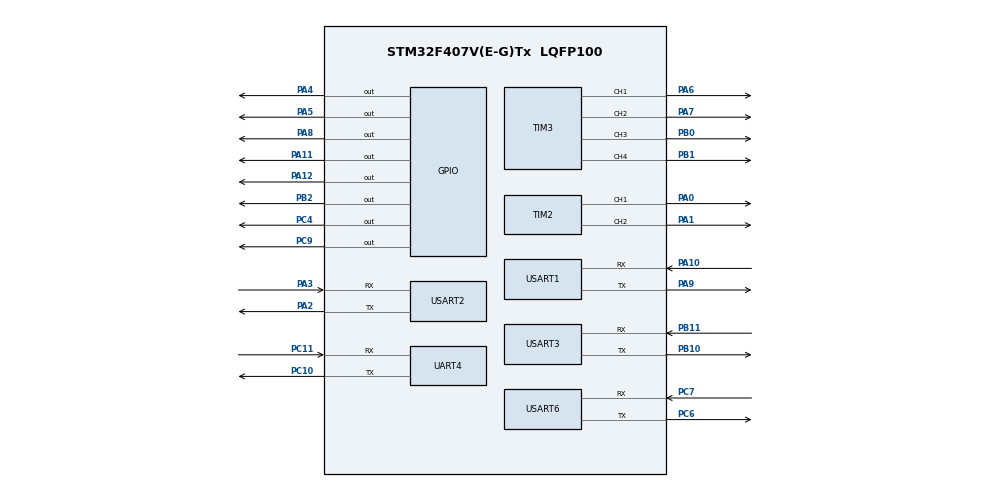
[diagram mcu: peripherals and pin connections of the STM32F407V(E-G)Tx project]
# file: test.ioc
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FREERTOS.Queues01=uart1_rx_queue,16,64,1,Dynamic,NULL,NULL;uart2_rx_queue,16,64,1,Dynamic,NULL,NULL;uart3_rx_queue,16,64,1,Dynamic,NULL,NULL;parsed_cmd_queue,16,64,1,Dynamic,NULL,NULL;status_queue,16,64,1,Dynamic,NULL,NULL
FREERTOS.Tasks01=defaultTask,24,128,StartDefaultTask,Default,NULL,Dynamic,NULL,NULL;Receive_Task,11,256,CommReceiveEntry,Default,NULL,Dynamic,NULL,NULL;Sensor_Task,12,512,SensorProcessEntry,Default,NULL,Dynamic,NULL,NULL;Control_Task,14,768,ControlEntry,Default,NULL,Dynamic,NULL,NULL;Send_Task,10,512,CommSendEntry,Default,NULL,Dynamic,NULL,NULL;Parse_Task,11,384,ParseEntry,Default,NULL,Dynamic,NULL,NULL;Status_Task,10,256,StatusEntry,Default,NULL,Dynamic,NULL,NULL
FREERTOS.configTOTAL_HEAP_SIZE=32768
Mcu.Family=STM32F4
Mcu.Name=STM32F407V(E-G)Tx
Mcu.Package=LQFP100
NVIC.PriorityGroup=NVIC_PRIORITYGROUP_4
NVIC.TIM1_UP_TIM10_IRQn=true\:15\:0\:false\:false\:true\:false\:false\:true\:true
NVIC.TimeBase=TIM1_UP_TIM10_IRQn
NVIC.TimeBaseIP=TIM1
NVIC.UART4_IRQn=true\:5\:0\:false\:false\:true\:true\:true\:true\:true
NVIC.USART1_IRQn=true\:5\:0\:false\:false\:true\:true\:true\:true\:true
NVIC.USART2_IRQn=true\:5\:0\:false\:false\:true\:true\:true\:true\:true
NVIC.USART3_IRQn=true\:5\:0\:false\:false\:true\:true\:true\:true\:true
NVIC.USART6_IRQn=true\:5\:0\:false\:false\:true\:true\:true\:true\:true
PA0-WKUP.Signal=S_TIM2_CH1_ETR
PA1.Signal=S_TIM2_CH2
PA10.Mode=Asynchronous
PA10.Signal=USART1_RX
PA11.GPIO_Speed=GPIO_SPEED_FREQ_MEDIUM
PA11.Signal=GPIO_Output
PA12.GPIO_Speed=GPIO_SPEED_FREQ_MEDIUM
PA12.Signal=GPIO_Output
PA13.Mode=Serial_Wire
PA13.Signal=SYS_JTMS-SWDIO
PA14.Mode=Serial_Wire
PA14.Signal=SYS_JTCK-SWCLK
PA2.Mode=Asynchronous
PA2.Signal=USART2_TX
PA3.Mode=Asynchronous
PA3.Signal=USART2_RX
PA4.GPIO_ModeDefaultOutputPP=GPIO_MODE_OUTPUT_OD
PA4.GPIO_PuPd=GPIO_NOPULL
PA4.GPIO_Speed=GPIO_SPEED_FREQ_HIGH
PA4.Signal=GPIO_Output
PA5.GPIO_ModeDefaultOutputPP=GPIO_MODE_OUTPUT_OD
PA5.GPIO_PuPd=GPIO_NOPULL
PA5.GPIO_Speed=GPIO_SPEED_FREQ_HIGH
PA5.Signal=GPIO_Output
PA6.Signal=S_TIM3_CH1
PA7.Signal=S_TIM3_CH2
PA8.GPIO_ModeDefaultOutputPP=GPIO_MODE_OUTPUT_OD
PA8.GPIO_PuPd=GPIO_NOPULL
PA8.GPIO_Speed=GPIO_SPEED_FREQ_HIGH
PA8.Signal=GPIO_Output
PA9.Mode=Asynchronous
PA9.Signal=USART1_TX
PB0.Signal=S_TIM3_CH3
PB1.Signal=S_TIM3_CH4
PB10.Mode=Asynchronous
PB10.Signal=USART3_TX
PB11.Mode=Asynchronous
PB11.Signal=USART3_RX
PB2.GPIO_Speed=GPIO_SPEED_FREQ_HIGH
PB2.Signal=GPIO_Output
PC10.Mode=Asynchronous
PC10.Signal=UART4_TX
PC11.Mode=Asynchronous
PC11.Signal=UART4_RX
PC4.GPIO_Speed=GPIO_SPEED_FREQ_MEDIUM
PC4.Signal=GPIO_Output
PC6.Mode=Asynchronous
PC6.Signal=USART6_TX
PC7.Mode=Asynchronous
PC7.Signal=USART6_RX
PC9.GPIO_ModeDefaultOutputPP=GPIO_MODE_OUTPUT_OD
PC9.GPIO_PuPd=GPIO_NOPULL
PC9.GPIO_Speed=GPIO_SPEED_FREQ_HIGH
PC9.Signal=GPIO_Output
PH0-OSC_IN.Mode=HSE-External-Oscillator
PH0-OSC_IN.Signal=RCC_OSC_IN
PH1-OSC_OUT.Mode=HSE-External-Oscillator
PH1-OSC_OUT.Signal=RCC_OSC_OUT
ProjectManager.HeapSize=0x200
ProjectManager.StackSize=0x400
ProjectManager.TargetToolchain=MDK-ARM V5.32
RCC.48MHZClocksFreq_Value=84000000
RCC.AHBFreq_Value=168000000
RCC.APB1CLKDivider=RCC_HCLK_DIV4
RCC.APB1Freq_Value=42000000
RCC.APB1TimFreq_Value=84000000
RCC.APB2CLKDivider=RCC_HCLK_DIV2
RCC.APB2Freq_Value=84000000
RCC.APB2TimFreq_Value=168000000
RCC.CortexFreq_Value=168000000
RCC.EnbaleCSS=true
RCC.HCLKFreq_Value=168000000
RCC.HSE_VALUE=8000000
RCC.HSI_VALUE=16000000
RCC.LSE_VALUE=32768
RCC.PLLM=4
RCC.PLLN=168
RCC.PLLSourceVirtual=RCC_PLLSOURCE_HSE
RCC.SYSCLKFreq_VALUE=168000000
RCC.SYSCLKSource=RCC_SYSCLKSOURCE_PLLCLK
RCC.VCOOutputFreq_Value=336000000
SH.S_TIM2_CH1_ETR.0=TIM2_CH1,PWM Generation1 CH1
SH.S_TIM2_CH2.0=TIM2_CH2,PWM Generation2 CH2
SH.S_TIM3_CH1.0=TIM3_CH1,PWM Generation1 CH1
SH.S_TIM3_CH2.0=TIM3_CH2,PWM Generation2 CH2
SH.S_TIM3_CH3.0=TIM3_CH3,PWM Generation3 CH3
SH.S_TIM3_CH4.0=TIM3_CH4,PWM Generation4 CH4
TIM2.Channel-PWM\ Generation1\ CH1=TIM_CHANNEL_1
TIM2.Channel-PWM\ Generation2\ CH2=TIM_CHANNEL_2
TIM3.Channel-PWM\ Generation1\ CH1=TIM_CHANNEL_1
TIM3.Channel-PWM\ Generation2\ CH2=TIM_CHANNEL_2
TIM3.Channel-PWM\ Generation3\ CH3=TIM_CHANNEL_3
TIM3.Channel-PWM\ Generation4\ CH4=TIM_CHANNEL_4
UART4.VirtualMode=Asynchronous
USART1.VirtualMode=VM_ASYNC
USART2.VirtualMode=VM_ASYNC
USART3.VirtualMode=VM_ASYNC
USART6.VirtualMode=VM_ASYNC
VP_FREERTOS_VS_CMSIS_V2.Mode=CMSIS_V2
VP_SYS_VS_tim1.Mode=TIM1
VP_TIM2_VS_ClockSourceINT.Mode=Internal
VP_TIM3_VS_ClockSourceINT.Mode=Internal
board=custom

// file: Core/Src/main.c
/* USER CODE BEGIN Header */
/**
  ******************************************************************************
  * @file           : main.c
  * @brief          : Main program body
  ******************************************************************************
  * @attention
  *
  * Copyright (c) 2025 STMicroelectronics.
  * All rights reserved.
  *
  * This software is licensed under terms that can be found in the LICENSE file
  * in the root directory of this software component.
  * If no LICENSE file comes with this software, it is provided AS-IS.
  *
  ******************************************************************************
  */
/* USER CODE END Header */
#include "main.h"
#include "cmsis_os.h"

#include "tim.h"
#include "usart.h"
#include "gpio.h"

/* USER CODE BEGIN Includes */
#include "stdio.h"
#include "string.h"
#include "RF1.H"
#include "bluebooth.h"
#include "servo.h"
/* USER CODE END Includes */

/* USER CODE BEGIN PD */
// 缓冲区 & 队列句柄
uint8_t uart1_rx_byte;
uint8_t uart1_rx_buf[CMD_LEN+1];
uint8_t uart1_rx_index = 0;
uint8_t uart6_rx_byte;
uint8_t uart3_rx_byte;
uint8_t uart3_rx_buffer[64];
uint8_t uart3_rx_index = 0;
extern osMessageQueueId_t uart1_rx_queueHandle;
extern osMessageQueueId_t uart3_rx_queueHandle;
/* USER CODE END PD */

void SystemClock_Config(void);
void MX_FREERTOS_Init(void);
/* USER CODE BEGIN PFP */
void CopeData(unsigned char ucData);
/* USER CODE END PFP */

/* USER CODE BEGIN 0 */
int fputc(int ch, FILE *f)
{
//	HAL_UART_Transmit(&huart2, (uint8_t *)&ch, 1, HAL_MAX_DELAY);
	HAL_UART_Transmit(&huart1, (uint8_t *)&ch, 1, HAL_MAX_DELAY);
    HAL_UART_Transmit(&huart3, (uint8_t *)&ch, 1, HAL_MAX_DELAY);
//	HAL_UART_Transmit(&huart4, (uint8_t *)&ch, 1, HAL_MAX_DELAY);
//	HAL_UART_Transmit(&huart6, (uint8_t *)&ch, 1, HAL_MAX_DELAY);
    return ch;
}

/* USER CODE END 0 */

int main(void)
{

  /* MCU Configuration--------------------------------------------------------*/

  /* Reset of all peripherals, Initializes the Flash interface and the Systick. */
  HAL_Init();

  /* Configure the system clock */
  SystemClock_Config();

  /* Initialize all configured peripherals */
  MX_GPIO_Init();
  MX_UART4_Init();
  MX_USART1_UART_Init();
  MX_USART6_UART_Init();
  MX_USART2_UART_Init();
  MX_USART3_UART_Init();
  MX_TIM2_Init();
  MX_TIM3_Init();
  /* USER CODE BEGIN 2 */
//  char testMsg[] = "USART2 Test: Hello World!\r\n";
//  uint8_t number = 42;
//  char numStr[10];
    HAL_Delay(100);  // 给IMU上电
//	Sensors_Init();
	HAL_UART_Receive_IT(&huart1, &uart1_rx_byte, 1);
	HAL_UART_Receive_IT(&huart6, &uart6_rx_byte, 1);
	HAL_UART_Receive_IT(&huart3, &uart3_rx_byte, 1);
	Sensors_Init();
	RF_Init();
	bluetooth_Init();
	Servo_Init();
	Motor_Init();
	set_pwm(&htim3, TIM_CHANNEL_1, 7.5f);
	set_pwm(&htim3, TIM_CHANNEL_2, 7.5f);
	set_pwm(&htim3, TIM_CHANNEL_3, 7.5f);
	set_pwm(&htim3, TIM_CHANNEL_4, 7.5f);

//  printf("IMU Initialization Started...\n");
  /* USER CODE END 2 */

  /* Init scheduler */
  osKernelInitialize();

  /* Call init function for freertos objects (in cmsis_os2.c) */
  MX_FREERTOS_Init();

  /* Start scheduler */
  osKernelStart();

  /* We should never get here as control is now taken by the scheduler */

  /* Infinite loop */
  while (1)
  {
    /* USER CODE BEGIN 3 */
//        HAL_UART_Transmit(&huart2, (uint8_t*)testMsg, strlen(testMsg), 100);

//        sprintf(numStr, "Decimal: %d\r\n", number);
//        HAL_UART_Transmit(&huart2, (uint8_t*)numStr, strlen(numStr), 100);

        HAL_Delay(1000);  //
  }
  /* USER CODE END 3 */
}

void SystemClock_Config(void)
{
  RCC_OscInitTypeDef RCC_OscInitStruct = {0};
  RCC_ClkInitTypeDef RCC_ClkInitStruct = {0};

  /** Configure the main internal regulator output voltage
  */
  __HAL_RCC_PWR_CLK_ENABLE();
  __HAL_PWR_VOLTAGESCALING_CONFIG(PWR_REGULATOR_VOLTAGE_SCALE1);

  /** Initializes the RCC Oscillators according to the specified parameters
  * in the RCC_OscInitTypeDef structure.
  */
  RCC_OscInitStruct.OscillatorType = RCC_OSCILLATORTYPE_HSE;
  RCC_OscInitStruct.HSEState = RCC_HSE_ON;
  RCC_OscInitStruct.PLL.PLLState = RCC_PLL_ON;
  RCC_OscInitStruct.PLL.PLLSource = RCC_PLLSOURCE_HSE;
  RCC_OscInitStruct.PLL.PLLM = 4;
  RCC_OscInitStruct.PLL.PLLN = 168;
  RCC_OscInitStruct.PLL.PLLP = RCC_PLLP_DIV2;
  RCC_OscInitStruct.PLL.PLLQ = 4;
  if (HAL_RCC_OscConfig(&RCC_OscInitStruct) != HAL_OK)
  {
    Error_Handler();
  }

  /** Initializes the CPU, AHB and APB buses clocks
  */
  RCC_ClkInitStruct.ClockType = RCC_CLOCKTYPE_HCLK|RCC_CLOCKTYPE_SYSCLK
                              |RCC_CLOCKTYPE_PCLK1|RCC_CLOCKTYPE_PCLK2;
  RCC_ClkInitStruct.SYSCLKSource = RCC_SYSCLKSOURCE_PLLCLK;
  RCC_ClkInitStruct.AHBCLKDivider = RCC_SYSCLK_DIV1;
  RCC_ClkInitStruct.APB1CLKDivider = RCC_HCLK_DIV2;
  RCC_ClkInitStruct.APB2CLKDivider = RCC_HCLK_DIV1;

  if (HAL_RCC_ClockConfig(&RCC_ClkInitStruct, FLASH_LATENCY_5) != HAL_OK)
  {
    Error_Handler();
  }

  /** Enables the Clock Security System
  */
  HAL_RCC_EnableCSS();

}

/* USER CODE BEGIN 4 */
// 中断回调：每收到一帧就入队
/* USER CODE BEGIN 4 */
void HAL_UART_RxCpltCallback(UART_HandleTypeDef *huart)
{
//    if (huart->Instance == USART2)
//    {
//        // 处理USART2接收
//        if (uart2_rx_byte == '\n' || uart2_rx_index >= QUEUE_MSG_SIZE - 1)
//        {
//            uart2_rx_buf[uart2_rx_index] = '\0';  // 结束符

//            // 拷贝缓冲内容，避免覆盖
//            char temp[QUEUE_MSG_SIZE] = {0};
//            memcpy(temp, uart2_rx_buf, QUEUE_MSG_SIZE);

//            // 入队列
//            osMessageQueuePut(uart2_rx_queueHandle, temp, 0, 0);

//            uart2_rx_index = 0;
//        }
//        else
//        {
//            uart2_rx_buf[uart2_rx_index++] = uart2_rx_byte;
//        }

//        // 继续接收下一个字节
//        HAL_UART_Receive_IT(&huart2, &uart2_rx_byte, 1);
//}
	if (huart->Instance == USART6)
    {
        // 处理IMU数据
        CopeData(uart6_rx_byte); // 调用IMU数据处理函数
        // 继续接收下一个字节
        HAL_UART_Receive_IT(&huart6, &uart6_rx_byte, 1);
	}
if (huart->Instance == USART3) {
    static uint8_t buffer[64];
    static uint8_t index = 0;

    // 检测结束符(回车或最大长度)
    if (uart3_rx_byte == '\n' || uart3_rx_byte == '\r') {
         if (index > 0) { // 确保有数据才处理
                buffer[index] = '\0';  // 确保终止符
                osMessageQueuePut(uart3_rx_queueHandle, buffer, 0, 0);
            }
            index = 0;  // 重置索引
    }
    // 处理可打印字符
    else if (uart3_rx_byte >= ' ' && uart3_rx_byte <= '~') {
			if (index < sizeof(buffer) - 1) {
                buffer[index++] = uart3_rx_byte;
            }
	}

//    // 重要修改：处理"GL"和"GR"指令
//    // 条件修正：添加对GL/GR指令的支持
//    if ((buffer[0] == 'G' && (buffer[1] == 'A' || buffer[1] == 'L' || buffer[1] == 'R')) ||
//        (buffer[0] == 'S' && buffer[1] == '4')) {
//        osMessageQueuePut(uart3_rx_queueHandle, buffer, 0, 0);
//    }

    HAL_UART_Receive_IT(huart, &uart3_rx_byte, 1);  // 重新启用接收
}
}

/* USER CODE END 4 *//* USER CODE END 4 */

void HAL_TIM_PeriodElapsedCallback(TIM_HandleTypeDef *htim)
{
  if (htim->Instance == TIM1)
  {
    HAL_IncTick();
  }
}

void Error_Handler(void)
{
  __disable_irq();
  while (1)
  {
  }
}

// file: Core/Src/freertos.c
/* USER CODE BEGIN Header */
/**
  ******************************************************************************
  * File Name          : freertos.c
  * Description        : Code for freertos applications
  ******************************************************************************
  * @attention
  *
  * Copyright (c) 2025 STMicroelectronics.
  * All rights reserved.
  *
  * This software is licensed under terms that can be found in the LICENSE file
  * in the root directory of this software component.
  * If no LICENSE file comes with this software, it is provided AS-IS.
  *
  ******************************************************************************
  */
/* USER CODE END Header */

#include "FreeRTOS.h"
#include "task.h"
#include "main.h"
#include "cmsis_os.h"

/* USER CODE BEGIN Includes */
#include "usart.h"
#include "stdio.h"
#include <string.h>
#include <stdlib.h>
/* USER CODE END Includes */

/* USER CODE BEGIN PTD */
#include "sensors.h"
#include "RF1.h"
#include "bluebooth.h"
#include "servo.h"
#include <stdarg.h>
typedef struct {
    RF_PacketType sensorType;  // 传感器类型标识
    union {
        IMU_Data imu;          // IMU传感器数据
        MS5837_Data depth;     // 深度传感器数据
        INA226_Data power;     // 电源传感器数据
    } data;
} SensorMessage_t;
extern volatile SwimDirection turn_direction;
volatile uint8_t Flag_Servo = 0xFF;
uint8_t Flag_X = 0;
uint8_t Flag_Z = 0xFF;
osMutexId_t servoMutex;
osMutexId_t cruiseMutex; 		// 新增巡航控制互斥锁
/* USER CODE END PTD */

/* USER CODE BEGIN Variables */
osMutexId_t uartMutex;  //串口输出互斥锁
/* USER CODE END Variables */
/* Definitions for defaultTask */
osThreadId_t defaultTaskHandle;
const osThreadAttr_t defaultTask_attributes = {
  .name = "defaultTask",
  .stack_size = 128 * 4,
  .priority = (osPriority_t) osPriorityNormal,
};

/* Definitions for Sensor_Task */
osThreadId_t Sensor_TaskHandle;
const osThreadAttr_t Sensor_Task_attributes = {
  .name = "Sensor_Task",
  .stack_size = 2048 * 4,
  .priority = (osPriority_t) osPriorityNormal,//原来是osPriorityNormal
};

/* Definitions for Parse_Task */
osThreadId_t Parse_TaskHandle;
const osThreadAttr_t Parse_Task_attributes = {
  .name = "Parse_Task",
  .stack_size = 384 * 4,
  .priority = (osPriority_t) osPriorityNormal1,
};
/* Definitions for Status_Task */
osThreadId_t Status_TaskHandle;
const osThreadAttr_t Status_Task_attributes = {
  .name = "Status_Task",
  .stack_size = 256 * 4,
  .priority = (osPriority_t) osPriorityLow2,
};
/* Definitions for uart1_rx_queue */
osMessageQueueId_t uart1_rx_queueHandle;
const osMessageQueueAttr_t uart1_rx_queue_attributes = {
  .name = "uart1_rx_queue"
};
/* Definitions for uart2_rx_queue */
osMessageQueueId_t uart2_rx_queueHandle;
const osMessageQueueAttr_t uart2_rx_queue_attributes = {
  .name = "uart2_rx_queue"
};
/* Definitions for uart3_rx_queue */
osMessageQueueId_t uart3_rx_queueHandle;
const osMessageQueueAttr_t uart3_rx_queue_attributes = {
  .name = "uart3_rx_queue"
};
/* Definitions for parsed_cmd_queue */
osMessageQueueId_t parsed_cmd_queueHandle;
const osMessageQueueAttr_t parsed_cmd_queue_attributes = {
  .name = "parsed_cmd_queue"
};
/* Definitions for status_queue */
osMessageQueueId_t status_queueHandle;
const osMessageQueueAttr_t status_queue_attributes = {
  .name = "status_queue"
};
osMessageQueueId_t servo_cmd_queueHandle;
const osMessageQueueAttr_t servo_cmd_queue_attributes = {
    .name = "servo_cmd_queue"
};
/* USER CODE BEGIN FunctionPrototypes */
void parse_command(const char *cmd, uint8_t port_id);
void SafePrintf(const char *format, ...);
void SafePrintf(const char *format, ...)
{
    if (osMutexAcquire(uartMutex,100) == osOK) {  // 最多等待100ms
        va_list args;
        va_start(args, format);
        vprintf(format, args);
        va_end(args);
        osMutexRelease(uartMutex);
    }
}
/* USER CODE END FunctionPrototypes */

void StartDefaultTask(void *argument);
void CommReceiveEntry(void *argument);
void SensorProcessEntry(void *argument);
void CommSendEntry(void *argument);
//void ParseEntry(void *argument);
//void StatusEntry(void *argument);
void MX_FREERTOS_Init(void); /* (MISRA C 2004 rule 8.1) */

void MX_FREERTOS_Init(void) {

  /* Create the queue(s) */
  /* creation of uart1_rx_queue */
  uart1_rx_queueHandle = osMessageQueueNew (16, 64, &uart1_rx_queue_attributes);

  /* creation of uart2_rx_queue */
  uart2_rx_queueHandle = osMessageQueueNew (16, QUEUE_MSG_SIZE, &uart2_rx_queue_attributes);

  /* creation of uart3_rx_queue */
  uart3_rx_queueHandle = osMessageQueueNew (16, 64, &uart3_rx_queue_attributes);

  /* creation of parsed_cmd_queue */
  parsed_cmd_queueHandle = osMessageQueueNew (16, 64, &parsed_cmd_queue_attributes);

  /* creation of status_queue */
  status_queueHandle = osMessageQueueNew (16, 64, &status_queue_attributes);

  /* Create the thread(s) */
  /* creation of defaultTask */
  defaultTaskHandle = osThreadNew(StartDefaultTask, NULL, &defaultTask_attributes);

  /* creation of Sensor_Task */
  Sensor_TaskHandle = osThreadNew(SensorProcessEntry, NULL, &Sensor_Task_attributes);

//  /* creation of Parse_Task */
//  Parse_TaskHandle = osThreadNew(ParseEntry, NULL, &Parse_Task_attributes);

//  /* creation of Status_Task */
//  Status_TaskHandle = osThreadNew(StatusEntry, NULL, &Status_Task_attributes);

uartMutex = osMutexNew(NULL);
  if (uartMutex == NULL) {
    // 互斥锁创建失败处理（系统关键错误）
    Error_Handler();
  }
  servoMutex = osMutexNew(NULL);
  cruiseMutex = osMutexNew(NULL);

}

void StartDefaultTask(void *argument)
{
  /* USER CODE BEGIN StartDefaultTask */
  /* Infinite loop */
  for(;;)
  {
		UpdatePropellers();
		osMutexAcquire(servoMutex, osWaitForever);
        uint8_t local_flag = Flag_Servo;
        SwimDirection local_turn_direction = turn_direction;
        osMutexRelease(servoMutex);
		// 获取当前巡航状态
		uint8_t cruise_active = 0;
		osMutexAcquire(cruiseMutex, osWaitForever);
		cruise_active = cruise_control.active;
		osMutexRelease(cruiseMutex);
	if (cruise_active) {
        // 巡航模式优先
        Cruise_Update(); // 在互斥锁保护下更新
    }
	else {
            if (local_turn_direction == DIRECTION_FORWARD) {
                Servo_ForwardTask();
            }
            else if (local_turn_direction == DIRECTION_LEFT ||
                     local_turn_direction == DIRECTION_RIGHT) {
                Servo_UpdateTask();
            }
            else if (local_turn_direction == DIRECTION_STOP) {
            // 确保舵机保持停止状态
            static uint32_t last_stop_check = 0;
            if (HAL_GetTick() - last_stop_check > 1000) {
                Servo_Stop(); // 每秒检查一次
                last_stop_check = HAL_GetTick();
            }
            }
		}
		if (Flag_Z == 0xFF) {
            // 未收到指令，保持初始值 8.5f
            static uint32_t last_check = 0;
            if(HAL_GetTick() - last_check > 1000) {
                set_pwm(&htim3, TIM_CHANNEL_4, 9.5f);
                last_check = HAL_GetTick();
            }
        }
	   else if (Flag_Z == 0)
	  {
		 set_pwm(&htim3, TIM_CHANNEL_4, 4.5f);
	  }
	  	  else if (Flag_Z == 1) {
		 set_pwm(&htim3, TIM_CHANNEL_4, 5.5f);
        }
	  	 else if (Flag_Z == 2) {
		set_pwm(&htim3, TIM_CHANNEL_4, 6.5f);
        }
		else if (Flag_Z == 3) {
        set_pwm(&htim3, TIM_CHANNEL_4, 7.5f);
    }
		else if (Flag_Z == 4) {
        set_pwm(&htim3, TIM_CHANNEL_4, 8.5f);
    }
	else if (Flag_Z == 5) {
        set_pwm(&htim3, TIM_CHANNEL_4, 9.5f);
    }
	 else if (Flag_Z == 6) {
        set_pwm(&htim3, TIM_CHANNEL_4, 10.5f);
    }
	 else if (Flag_Z == 7) {
        set_pwm(&htim3, TIM_CHANNEL_4, 11.5f);
    }
	else if (Flag_Z == 8) {
        set_pwm(&htim3, TIM_CHANNEL_4, 13.5f);
    }
	else if (Flag_Z == 9) {
        set_pwm(&htim3, TIM_CHANNEL_4, 35.5f);
    } osDelay(10);
	}
}
  /* USER CODE END StartDefaultTask */

void CommReceiveEntry(void *argument)
{
  /* USER CODE BEGIN CommReceiveEntry */
  /* Infinite loop */
	char rx_buffer[64]; // 使用局部缓冲区
    for (;;) {
        if (osMessageQueueGet(uart3_rx_queueHandle, rx_buffer, NULL, 50) == osOK) {
            // 快速处理指令

            char cmd[3] = {rx_buffer[0], rx_buffer[1],  '\0'};
            parse_command(cmd, 2);
        }

        osDelay(50);
    }
}

void SensorProcessEntry(void *argument)
{
	/* USER CODE BEGIN SensorProcessEntry */
	/* Infinite loop */
	SensorData_t sensor_data;
	TickType_t lastWakeTime = xTaskGetTickCount();
  for(;;)
  {
// 读取传感器数据
    Sensor_ReadAll(&sensor_data);
// 使用单个printf输出所有关键传感器数据
		SafePrintf(
            "fish_attitude: {\n"
            "  roll: %.10f,\n"
            "  pitch: %.10f,\n"
            "  yaw: %.10f,\n"
            "  roll_speed: %.10f,\n"
            "  pitch_speed: %.10f,\n"
            "  yaw_speed: %.10f\n"
            "},\n"
            "depth_sensor: {"
            "  depth: %.4fcm,"
            "  temperature: %.2f,"
            "  pressure: %.2fpa"
            "},\n"
            "power_sensor: {"
            "  voltage: %umV,"
            "  current: %umA,"
            "  power: %umW""},\n",
            // 姿态数据
            sensor_data.roll,
            sensor_data.pitch,
            sensor_data.yaw,
            sensor_data.wx,
            sensor_data.wy,
            sensor_data.wz,
            // 深度传感器数据
            sensor_data.depth,
            sensor_data.temperature,
            sensor_data.pressure,
          // 电源传感器数据
            sensor_data.bus_voltage,
            sensor_data.current,
            sensor_data.power
			);
	vTaskDelayUntil(&lastWakeTime, pdMS_TO_TICKS(10));
  }

  /* USER CODE END SensorProcessEntry */
}

void parse_command(const char *cmd, uint8_t port_id)
{
// 仅打印原始指令

	SafePrintf("CMD: %s\r\n", cmd);

	if (strlen(cmd) == 2)
    {
        // D系列指令 - 舵机控制
        if (cmd[0] == 'D') {
            osMutexAcquire(servoMutex, osWaitForever);

            switch(cmd[1]) {
                case '0': // 停止
					Flag_Servo = 0;
                    turn_direction = DIRECTION_STOP;
                    Servo_Stop();  // 直接调用停止函数
                    printf("Servo stop command received\n");
                    break;

                case '1': // 前进
                    Flag_Servo = 1;
                    turn_direction = DIRECTION_FORWARD;
                    // 重置状态机
                    current_state_x = PWM_STATE_DUTY1;
                    last_jiao_switch_time = HAL_GetTick();
                    printf("Servo forward command received\n");
                    break;

                case '2': // 左转
                    Flag_Servo = 2;
					turn_direction = DIRECTION_LEFT;
                    current_state_x = PWM_STATE_DUTY1;
                    last_jiao_switch_time = HAL_GetTick();
				printf("Servo left turn command received\n");
                    break;

                case '3': // 右转
                    Flag_Servo = 3;
					turn_direction = DIRECTION_RIGHT;
                    current_state_x = PWM_STATE_DUTY1;
                    last_jiao_switch_time = HAL_GetTick();
				printf("Servo right turn command received\n");
                    break;
            }

            osMutexRelease(servoMutex);

            // 确保停止巡航
            osMutexAcquire(cruiseMutex, osWaitForever);
            cruise_control.active = 0;
			cruise_control.state = CRUISE_IDLE;
            osMutexRelease(cruiseMutex);
        }

		if (cmd[0] == 'X' && cmd[1] == '0')
		{ControlPropellers(PROPELLER_STOP);}

		else if (cmd[0] == 'X' && cmd[1] == '1')
		{ControlPropellers(PROPELLER_FORWARD);}
		else if (cmd[0] == 'X' && cmd[1] == '2')
		{ControlPropellers(PROPELLER_REVERSE);}

		if (cmd[0] == 'Z' && cmd[1] == '0')
		Flag_Z = 0;
		else if (cmd[0] == 'Z' && cmd[1] == '1')
		Flag_Z = 1;
		else if (cmd[0] == 'Z' && cmd[1] == '2')
		Flag_Z = 2;
		else if (cmd[0] == 'Z' && cmd[1] == '3')
		Flag_Z = 3;
		else if (cmd[0] == 'Z' && cmd[1] == '4')
		Flag_Z = 4;
		else if (cmd[0] == 'Z' && cmd[1] == '5')
		Flag_Z = 5;
		else if (cmd[0] == 'Z' && cmd[1] == '6')
		Flag_Z = 6;
		else if (cmd[0] == 'Z' && cmd[1] == '7')
		Flag_Z = 7;
		else if (cmd[0] == 'Z' && cmd[1] == '8')
		Flag_Z = 8;
		else if (cmd[0] == 'Z' && cmd[1] == '9')
		Flag_Z = 9;
		if(cmd[0] == 'C' && cmd[1] == 'L')
		Cruise_Start(CRUISE_LEFT);
		else if(cmd[0] == 'C' && cmd[1] == 'R')
		 Cruise_Start(CRUISE_RIGHT);
		else if(cmd[0] == 'C' && cmd[1] == 'S')
		Cruise_Stop();
		if(cmd[0] == 'P' && cmd[1] == '0')
		{cruise_control.pid.Kp = 0.5f;
                    cruise_control.pid.Ki = 0.01f;
                    cruise_control.pid.Kd = 0.05f;
		printf("PID参数: [0.5,0.01,0.05]\n");
		// 重置积分项
		cruise_control.pid.integral = 0.0f;
		cruise_control.pid.prev_error = 0.0f;}
		else if(cmd[0] == 'P' && cmd[1] == '1')
		{cruise_control.pid.Kp = 0.8f;
                    cruise_control.pid.Ki = 0.02f;
                    cruise_control.pid.Kd = 0.1f;
                    printf("PID参数: [0.8,0.02,0.1]\n");
		// 重置积分项
    cruise_control.pid.integral = 0.0f;
    cruise_control.pid.prev_error = 0.0f;}
		else if(cmd[0] == 'P' && cmd[1] == '2')
		{
			cruise_control.pid.Kp = 1.2f;
                    cruise_control.pid.Ki = 0.03f;
                    cruise_control.pid.Kd = 0.15f;
                    printf("PID参数:[1.2,0.03,0.15]\n");
				// 重置积分项
				cruise_control.pid.integral = 0.0f;
				cruise_control.pid.prev_error = 0.0f;
		}
		if(cmd[0] == 'T' && cmd[1] == '0')
		cruise_control.target_turn_rate = 30.0f;
		else if(cmd[0] == 'T' && cmd[1] == '1')
		cruise_control.target_turn_rate = 35.0f;
		else if(cmd[0] == 'T' && cmd[1] == '2')
		cruise_control.target_turn_rate = 40.0f;
		else if(cmd[0] == 'T' && cmd[1] == '3')
		cruise_control.target_turn_rate = 45.0f;
		else if(cmd[0] == 'T' && cmd[1] == '4')
		cruise_control.target_turn_rate = 50.0f;
		else if(cmd[0] == 'T' && cmd[1] == '5')
		cruise_control.target_turn_rate = 55.0f;
		printf("转弯速率设为: %.1f°/s\n", cruise_control.target_turn_rate);
	}
}
